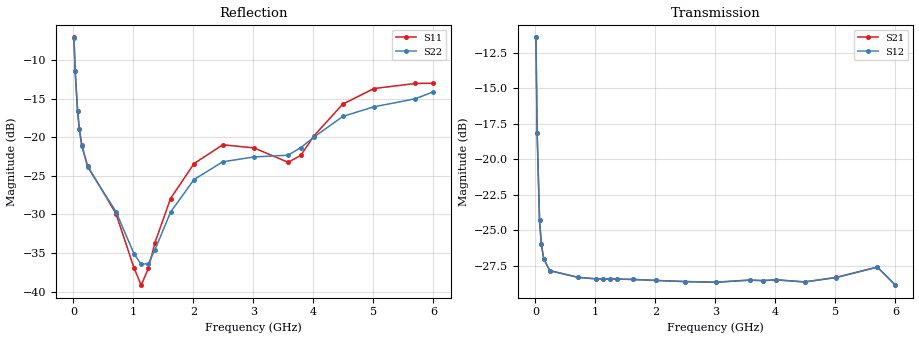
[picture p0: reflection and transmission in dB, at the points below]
! Integrated Device Technology
! Corporate Headquarters
! 6024 Silver Creek Valley Road
! San Jose, CA 95138  USA
! Phone:  1-408-284-8200
! Toll Free:  1-800-223-1366
! Webpage:  http://www.idt.com/
! Timing and RF Division
! 515 Groton Road, Suite 102
! Westford, MA 01886-6024
! Device:  F1951
! Description: 6-bit 0.5 dB Digital Step Attenuator
! Frequency:  100.0 -  4000.00 MHz
! Package:  4x4 mm Thin QFN Plastic Package: 24 pin
! Ports:  2 RF, 6 DC
!  Pin  1  = NC
!  Pin  2  = RF1  =  Port 1
!  Pin  3  = GND
!  Pin  4  = NC
!  Pin  5  = Serial Data Out (SDO)
!  Pin  6  = NC
!  Pin  7  = Reset Bar ( RSTb)
!  Pin  8  = Clock (CLK)
!  Pin  9  = Chip Select Bar (CSb)
!  Pin 10  = NC
!  Pin 11  = Serial Data In (SDI)
!  Pin 12  = NC
!  Pin 13  = NC
!  Pin 14  = VDD
!  Pin 15  = NC
!  Pin 16  = GND
!  Pin 17  = RF2  =  Port 2
!  Pin 18  = NC
!  Pin 19  = GND
!  Pin 20  = GND
!  Pin 21  = GND
!  Pin 22  = GND
!  Pin 23  = GND
!  Pin 24  = GND
! State:  55
! Atten State:  27.5 dB
! Voltage:  +3.30 Volts
! Current:  0.485 mA
! Data:  The device was measured on a F195X evaluation board which has
!  individual transmission lines to the RF pins.  Data was collected
!  de-embedded using a Automatic Fixture Removal [AFR] (Keysight Technologies).
!  The reference plane is the edge of the package pin.
! Misc:  Lot Code  1225BCA
!  Action Tracker AT0399
! Date Measured:  2018-09-13
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# GHz S dB R 50
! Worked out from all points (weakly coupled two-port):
!   600 points, 10 MHz to 6 GHz, reference 50 ohm
!   highest |S21| = -11.41 dB at 10 MHz (marker M1); lowest = -28.9 dB at 6 GHz (marker M2)
!   lowest |S11| = -39.2 dB at 1.13 GHz (marker M3), VSWR 1.02, Z = 48.9 + j0.171 ohm
!   |S11| at or under -10 dB: 22.7 MHz to end of sweep
!   |S22| runs from -36.9 to -7.1 dB; largest |S21 - S12| = 0.00014
!   S11 on the Smith chart (normalised r, x): 10 MHz: 1.72, -1.08; 30 MHz: 1.14, -0.58; 70 MHz: 0.97, -0.30; 1.36 GHz: 0.98, +0.04; 6 GHz: 0.81, +0.36
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0.01  -7.06 -34.6  -11.41 -40.8  -11.41 -40.8  -7.15 -34.6
0.03  -11.39 -61.4  -18.13 -57.9  -18.13 -57.9  -11.45 -61.3
0.07  -16.54 -86.5  -24.29 -48.3  -24.30 -48.3  -16.62 -86.5
0.1  -18.93 -97.3  -26.00 -39.3  -26.00 -39.2  -18.98 -97.4
0.14  -21.01 -107.7  -27.02 -31.1  -27.02 -31.0  -21.09 -107.3
0.24  -23.75 -122.1  -27.85 -21.0  -27.85 -21.0  -23.89 -122.0
0.71  -29.89 -134.8  -28.32 -14.5  -28.32 -14.6  -29.64 -137.6
1.01  -36.92 -154.8  -28.43 -16.0  -28.43 -16.0  -35.09 -152.1
1.13  -39.16 170.9  -28.44 -16.6  -28.44 -16.6  -36.47 -170.4
1.25  -37.00 134.9  -28.44 -17.5  -28.44 -17.5  -36.37 165.9
1.36  -33.65 120.4  -28.44 -18.5  -28.44 -18.5  -34.58 148.5
1.62  -27.94 115.0  -28.47 -20.7  -28.47 -20.7  -29.70 132.3
2.01  -23.42 123.0  -28.54 -24.6  -28.54 -24.6  -25.48 133.9
2.49  -20.97 136.1  -28.62 -29.2  -28.62 -29.2  -23.18 141.3
3.01  -21.38 146.3  -28.67 -34.0  -28.66 -33.9  -22.55 144.7
3.58  -23.25 125.1  -28.51 -39.2  -28.52 -39.2  -22.33 127.4
3.79  -22.35 109.2  -28.55 -41.2  -28.56 -41.1  -21.34 120.6
4.01  -19.82 100.7  -28.50 -43.2  -28.49 -43.2  -19.98 115.3
4.49  -15.70 99.1  -28.65 -47.3  -28.64 -47.2  -17.30 113.7
5.01  -13.69 107.9  -28.33 -49.2  -28.34 -49.2  -16.06 116.2
5.7  -13.03 113.0  -27.60 -60.6  -27.60 -60.6  -15.01 109.0
6  -13.00 106.8  -28.87 -62.3  -28.86 -62.2  -14.11 105.2
